VERSION 5.7 ;
  NOWIREEXTENSIONATPIN ON ;
  DIVIDERCHAR "/" ;
  BUSBITCHARS "[]" ;
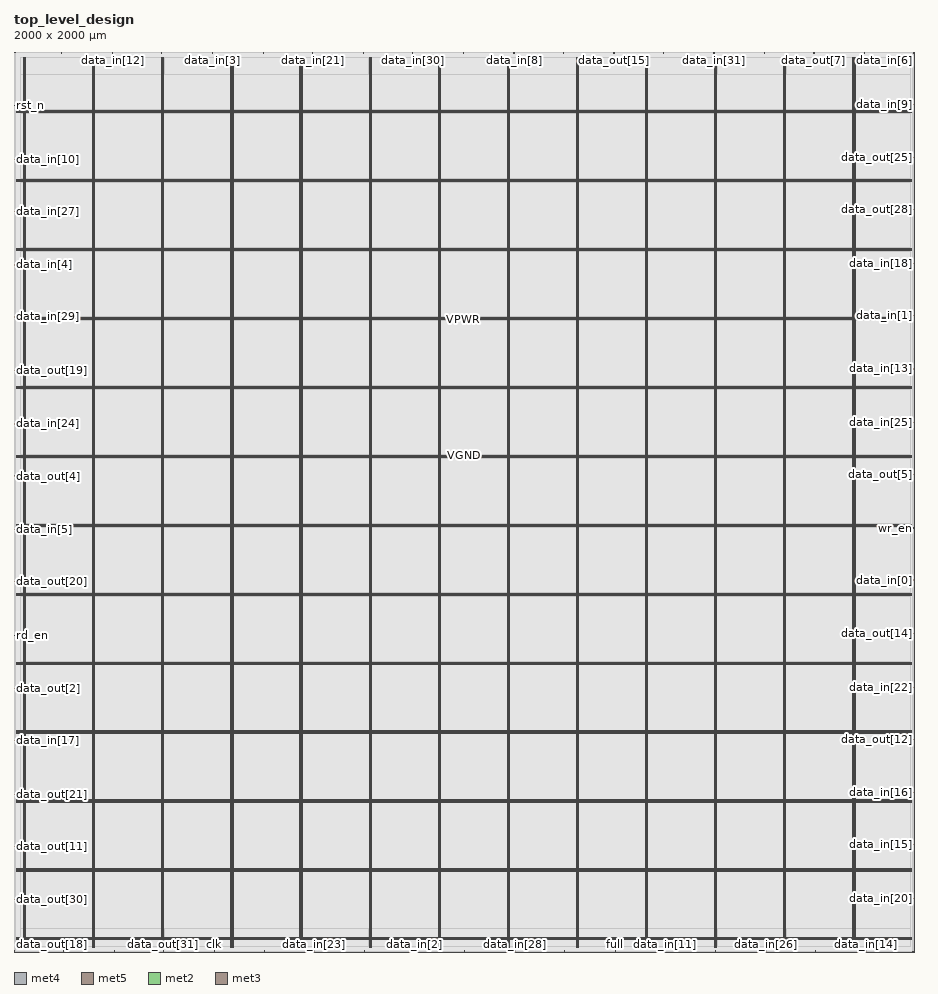
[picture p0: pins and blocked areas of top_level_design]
MACRO top_level_design
  CLASS BLOCK ;
  FOREIGN top_level_design ;
  ORIGIN 0.000 0.000 ;
  SIZE 2000.000 BY 2000.000 ;
  PIN VGND
    DIRECTION INOUT ;
    USE GROUND ;
    PORT
      LAYER met4 ;
        RECT 24.340 10.640 25.940 1988.560 ;
    END
    PORT
      LAYER met4 ;
        RECT 177.940 10.640 179.540 1988.560 ;
    END
    PORT
      LAYER met4 ;
        RECT 331.540 10.640 333.140 1988.560 ;
    END
    PORT
      LAYER met4 ;
        RECT 485.140 10.640 486.740 1988.560 ;
    END
    PORT
      LAYER met4 ;
        RECT 638.740 10.640 640.340 1988.560 ;
    END
    PORT
      LAYER met4 ;
        RECT 792.340 10.640 793.940 1988.560 ;
    END
    PORT
      LAYER met4 ;
        RECT 945.940 10.640 947.540 1988.560 ;
    END
    PORT
      LAYER met4 ;
        RECT 1099.540 10.640 1101.140 1988.560 ;
    END
    PORT
      LAYER met4 ;
        RECT 1253.140 10.640 1254.740 1988.560 ;
    END
    PORT
      LAYER met4 ;
        RECT 1406.740 10.640 1408.340 1988.560 ;
    END
    PORT
      LAYER met4 ;
        RECT 1560.340 10.640 1561.940 1988.560 ;
    END
    PORT
      LAYER met4 ;
        RECT 1713.940 10.640 1715.540 1988.560 ;
    END
    PORT
      LAYER met4 ;
        RECT 1867.540 10.640 1869.140 1988.560 ;
    END
    PORT
      LAYER met5 ;
        RECT 5.280 30.030 1994.340 31.630 ;
    END
    PORT
      LAYER met5 ;
        RECT 5.280 183.210 1994.340 184.810 ;
    END
    PORT
      LAYER met5 ;
        RECT 5.280 336.390 1994.340 337.990 ;
    END
    PORT
      LAYER met5 ;
        RECT 5.280 489.570 1994.340 491.170 ;
    END
    PORT
      LAYER met5 ;
        RECT 5.280 642.750 1994.340 644.350 ;
    END
    PORT
      LAYER met5 ;
        RECT 5.280 795.930 1994.340 797.530 ;
    END
    PORT
      LAYER met5 ;
        RECT 5.280 949.110 1994.340 950.710 ;
    END
    PORT
      LAYER met5 ;
        RECT 5.280 1102.290 1994.340 1103.890 ;
    END
    PORT
      LAYER met5 ;
        RECT 5.280 1255.470 1994.340 1257.070 ;
    END
    PORT
      LAYER met5 ;
        RECT 5.280 1408.650 1994.340 1410.250 ;
    END
    PORT
      LAYER met5 ;
        RECT 5.280 1561.830 1994.340 1563.430 ;
    END
    PORT
      LAYER met5 ;
        RECT 5.280 1715.010 1994.340 1716.610 ;
    END
    PORT
      LAYER met5 ;
        RECT 5.280 1868.190 1994.340 1869.790 ;
    END
  END VGND
  PIN VPWR
    DIRECTION INOUT ;
    USE POWER ;
    PORT
      LAYER met4 ;
        RECT 21.040 10.640 22.640 1988.560 ;
    END
    PORT
      LAYER met4 ;
        RECT 174.640 10.640 176.240 1988.560 ;
    END
    PORT
      LAYER met4 ;
        RECT 328.240 10.640 329.840 1988.560 ;
    END
    PORT
      LAYER met4 ;
        RECT 481.840 10.640 483.440 1988.560 ;
    END
    PORT
      LAYER met4 ;
        RECT 635.440 10.640 637.040 1988.560 ;
    END
    PORT
      LAYER met4 ;
        RECT 789.040 10.640 790.640 1988.560 ;
    END
    PORT
      LAYER met4 ;
        RECT 942.640 10.640 944.240 1988.560 ;
    END
    PORT
      LAYER met4 ;
        RECT 1096.240 10.640 1097.840 1988.560 ;
    END
    PORT
      LAYER met4 ;
        RECT 1249.840 10.640 1251.440 1988.560 ;
    END
    PORT
      LAYER met4 ;
        RECT 1403.440 10.640 1405.040 1988.560 ;
    END
    PORT
      LAYER met4 ;
        RECT 1557.040 10.640 1558.640 1988.560 ;
    END
    PORT
      LAYER met4 ;
        RECT 1710.640 10.640 1712.240 1988.560 ;
    END
    PORT
      LAYER met4 ;
        RECT 1864.240 10.640 1865.840 1988.560 ;
    END
    PORT
      LAYER met5 ;
        RECT 5.280 26.730 1994.340 28.330 ;
    END
    PORT
      LAYER met5 ;
        RECT 5.280 179.910 1994.340 181.510 ;
    END
    PORT
      LAYER met5 ;
        RECT 5.280 333.090 1994.340 334.690 ;
    END
    PORT
      LAYER met5 ;
        RECT 5.280 486.270 1994.340 487.870 ;
    END
    PORT
      LAYER met5 ;
        RECT 5.280 639.450 1994.340 641.050 ;
    END
    PORT
      LAYER met5 ;
        RECT 5.280 792.630 1994.340 794.230 ;
    END
    PORT
      LAYER met5 ;
        RECT 5.280 945.810 1994.340 947.410 ;
    END
    PORT
      LAYER met5 ;
        RECT 5.280 1098.990 1994.340 1100.590 ;
    END
    PORT
      LAYER met5 ;
        RECT 5.280 1252.170 1994.340 1253.770 ;
    END
    PORT
      LAYER met5 ;
        RECT 5.280 1405.350 1994.340 1406.950 ;
    END
    PORT
      LAYER met5 ;
        RECT 5.280 1558.530 1994.340 1560.130 ;
    END
    PORT
      LAYER met5 ;
        RECT 5.280 1711.710 1994.340 1713.310 ;
    END
    PORT
      LAYER met5 ;
        RECT 5.280 1864.890 1994.340 1866.490 ;
    END
  END VPWR
  PIN clk
    DIRECTION INPUT ;
    USE SIGNAL ;
    ANTENNAGATEAREA 1.286700 ;
    ANTENNADIFFAREA 0.434700 ;
    PORT
      LAYER met2 ;
        RECT 444.450 0.000 444.730 4.000 ;
    END
  END clk
  PIN data_in[0]
    DIRECTION INPUT ;
    USE SIGNAL ;
    ANTENNAGATEAREA 0.495000 ;
    PORT
      LAYER met3 ;
        RECT 1996.000 826.240 2000.000 826.840 ;
    END
  END data_in[0]
  PIN data_in[10]
    DIRECTION INPUT ;
    USE SIGNAL ;
    ANTENNAGATEAREA 0.990000 ;
    PORT
      LAYER met3 ;
        RECT 0.000 1761.240 4.000 1761.840 ;
    END
  END data_in[10]
  PIN data_in[11]
    DIRECTION INPUT ;
    USE SIGNAL ;
    ANTENNAGATEAREA 0.742500 ;
    PORT
      LAYER met2 ;
        RECT 1445.870 0.000 1446.150 4.000 ;
    END
  END data_in[11]
  PIN data_in[12]
    DIRECTION INPUT ;
    USE SIGNAL ;
    ANTENNAGATEAREA 0.990000 ;
    PORT
      LAYER met2 ;
        RECT 219.050 1996.000 219.330 2000.000 ;
    END
  END data_in[12]
  PIN data_in[13]
    DIRECTION INPUT ;
    USE SIGNAL ;
    ANTENNAGATEAREA 0.426000 ;
    PORT
      LAYER met3 ;
        RECT 1996.000 1295.440 2000.000 1296.040 ;
    END
  END data_in[13]
  PIN data_in[14]
    DIRECTION INPUT ;
    USE SIGNAL ;
    ANTENNAGATEAREA 0.990000 ;
    PORT
      LAYER met2 ;
        RECT 1893.450 0.000 1893.730 4.000 ;
    END
  END data_in[14]
  PIN data_in[15]
    DIRECTION INPUT ;
    USE SIGNAL ;
    ANTENNAGATEAREA 0.852000 ;
    PORT
      LAYER met3 ;
        RECT 1996.000 238.040 2000.000 238.640 ;
    END
  END data_in[15]
  PIN data_in[16]
    DIRECTION INPUT ;
    USE SIGNAL ;
    ANTENNAGATEAREA 0.852000 ;
    PORT
      LAYER met3 ;
        RECT 1996.000 353.640 2000.000 354.240 ;
    END
  END data_in[16]
  PIN data_in[17]
    DIRECTION INPUT ;
    USE SIGNAL ;
    ANTENNAGATEAREA 0.990000 ;
    PORT
      LAYER met3 ;
        RECT 0.000 469.240 4.000 469.840 ;
    END
  END data_in[17]
  PIN data_in[18]
    DIRECTION INPUT ;
    USE SIGNAL ;
    ANTENNAGATEAREA 0.495000 ;
    PORT
      LAYER met3 ;
        RECT 1996.000 1530.040 2000.000 1530.640 ;
    END
  END data_in[18]
  PIN data_in[19]
    DIRECTION INPUT ;
    USE SIGNAL ;
    ANTENNAGATEAREA 0.990000 ;
    PORT
      LAYER met3 ;
        RECT 0.000 1999.240 4.000 1999.840 ;
    END
  END data_in[19]
  PIN data_in[1]
    DIRECTION INPUT ;
    USE SIGNAL ;
    ANTENNAGATEAREA 0.247500 ;
    PORT
      LAYER met3 ;
        RECT 1996.000 1414.440 2000.000 1415.040 ;
    END
  END data_in[1]
  PIN data_in[20]
    DIRECTION INPUT ;
    USE SIGNAL ;
    ANTENNAGATEAREA 0.990000 ;
    PORT
      LAYER met3 ;
        RECT 1996.000 119.040 2000.000 119.640 ;
    END
  END data_in[20]
  PIN data_in[21]
    DIRECTION INPUT ;
    USE SIGNAL ;
    ANTENNAGATEAREA 0.990000 ;
    PORT
      LAYER met2 ;
        RECT 663.410 1996.000 663.690 2000.000 ;
    END
  END data_in[21]
  PIN data_in[22]
    DIRECTION INPUT ;
    USE SIGNAL ;
    ANTENNAGATEAREA 0.742500 ;
    PORT
      LAYER met3 ;
        RECT 1996.000 588.240 2000.000 588.840 ;
    END
  END data_in[22]
  PIN data_in[23]
    DIRECTION INPUT ;
    USE SIGNAL ;
    ANTENNAGATEAREA 0.990000 ;
    PORT
      LAYER met2 ;
        RECT 666.630 0.000 666.910 4.000 ;
    END
  END data_in[23]
  PIN data_in[24]
    DIRECTION INPUT ;
    USE SIGNAL ;
    ANTENNAGATEAREA 0.990000 ;
    PORT
      LAYER met3 ;
        RECT 0.000 1173.040 4.000 1173.640 ;
    END
  END data_in[24]
  PIN data_in[25]
    DIRECTION INPUT ;
    USE SIGNAL ;
    ANTENNAGATEAREA 0.247500 ;
    PORT
      LAYER met3 ;
        RECT 1996.000 1176.440 2000.000 1177.040 ;
    END
  END data_in[25]
  PIN data_in[26]
    DIRECTION INPUT ;
    USE SIGNAL ;
    ANTENNAGATEAREA 0.852000 ;
    PORT
      LAYER met2 ;
        RECT 1671.270 0.000 1671.550 4.000 ;
    END
  END data_in[26]
  PIN data_in[27]
    DIRECTION INPUT ;
    USE SIGNAL ;
    ANTENNAGATEAREA 0.990000 ;
    PORT
      LAYER met3 ;
        RECT 0.000 1645.640 4.000 1646.240 ;
    END
  END data_in[27]
  PIN data_in[28]
    DIRECTION INPUT ;
    USE SIGNAL ;
    ANTENNAGATEAREA 0.852000 ;
    PORT
      LAYER met2 ;
        RECT 1114.210 0.000 1114.490 4.000 ;
    END
  END data_in[28]
  PIN data_in[29]
    DIRECTION INPUT ;
    USE SIGNAL ;
    ANTENNAGATEAREA 0.990000 ;
    PORT
      LAYER met3 ;
        RECT 0.000 1411.040 4.000 1411.640 ;
    END
  END data_in[29]
  PIN data_in[2]
    DIRECTION INPUT ;
    USE SIGNAL ;
    ANTENNAGATEAREA 0.990000 ;
    PORT
      LAYER met2 ;
        RECT 888.810 0.000 889.090 4.000 ;
    END
  END data_in[2]
  PIN data_in[30]
    DIRECTION INPUT ;
    USE SIGNAL ;
    ANTENNAGATEAREA 0.852000 ;
    PORT
      LAYER met2 ;
        RECT 885.590 1996.000 885.870 2000.000 ;
    END
  END data_in[30]
  PIN data_in[31]
    DIRECTION INPUT ;
    USE SIGNAL ;
    ANTENNAGATEAREA 0.495000 ;
    PORT
      LAYER met2 ;
        RECT 1555.350 1996.000 1555.630 2000.000 ;
    END
  END data_in[31]
  PIN data_in[3]
    DIRECTION INPUT ;
    USE SIGNAL ;
    ANTENNAGATEAREA 0.990000 ;
    PORT
      LAYER met2 ;
        RECT 441.230 1996.000 441.510 2000.000 ;
    END
  END data_in[3]
  PIN data_in[4]
    DIRECTION INPUT ;
    USE SIGNAL ;
    ANTENNAGATEAREA 0.990000 ;
    PORT
      LAYER met3 ;
        RECT 0.000 1526.640 4.000 1527.240 ;
    END
  END data_in[4]
  PIN data_in[5]
    DIRECTION INPUT ;
    USE SIGNAL ;
    ANTENNAGATEAREA 0.990000 ;
    PORT
      LAYER met3 ;
        RECT 0.000 938.440 4.000 939.040 ;
    END
  END data_in[5]
  PIN data_in[6]
    DIRECTION INPUT ;
    USE SIGNAL ;
    ANTENNAGATEAREA 0.742500 ;
    PORT
      LAYER met2 ;
        RECT 1999.710 1996.000 1999.990 2000.000 ;
    END
  END data_in[6]
  PIN data_in[7]
    DIRECTION INPUT ;
    USE SIGNAL ;
    ANTENNAGATEAREA 0.990000 ;
    PORT
      LAYER met2 ;
        RECT 1780.750 0.000 1781.030 4.000 ;
    END
  END data_in[7]
  PIN data_in[8]
    DIRECTION INPUT ;
    USE SIGNAL ;
    ANTENNAGATEAREA 0.495000 ;
    PORT
      LAYER met2 ;
        RECT 1110.990 1996.000 1111.270 2000.000 ;
    END
  END data_in[8]
  PIN data_in[9]
    DIRECTION INPUT ;
    USE SIGNAL ;
    ANTENNAGATEAREA 0.742500 ;
    PORT
      LAYER met3 ;
        RECT 1996.000 1883.640 2000.000 1884.240 ;
    END
  END data_in[9]
  PIN data_out[0]
    DIRECTION OUTPUT TRISTATE ;
    USE SIGNAL ;
    ANTENNADIFFAREA 0.795200 ;
    PORT
      LAYER met2 ;
        RECT 1558.570 0.000 1558.850 4.000 ;
    END
  END data_out[0]
  PIN data_out[10]
    DIRECTION OUTPUT TRISTATE ;
    USE SIGNAL ;
    ANTENNADIFFAREA 0.795200 ;
    PORT
      LAYER met2 ;
        RECT 998.290 1996.000 998.570 2000.000 ;
    END
  END data_out[10]
  PIN data_out[11]
    DIRECTION OUTPUT TRISTATE ;
    USE SIGNAL ;
    ANTENNADIFFAREA 0.795200 ;
    PORT
      LAYER met3 ;
        RECT 0.000 234.640 4.000 235.240 ;
    END
  END data_out[11]
  PIN data_out[12]
    DIRECTION OUTPUT TRISTATE ;
    USE SIGNAL ;
    ANTENNADIFFAREA 0.445500 ;
    PORT
      LAYER met3 ;
        RECT 1996.000 472.640 2000.000 473.240 ;
    END
  END data_out[12]
  PIN data_out[13]
    DIRECTION OUTPUT TRISTATE ;
    USE SIGNAL ;
    ANTENNADIFFAREA 0.795200 ;
    PORT
      LAYER met2 ;
        RECT 1223.690 0.000 1223.970 4.000 ;
    END
  END data_out[13]
  PIN data_out[14]
    DIRECTION OUTPUT TRISTATE ;
    USE SIGNAL ;
    ANTENNADIFFAREA 0.445500 ;
    PORT
      LAYER met3 ;
        RECT 1996.000 707.240 2000.000 707.840 ;
    END
  END data_out[14]
  PIN data_out[15]
    DIRECTION OUTPUT TRISTATE ;
    USE SIGNAL ;
    ANTENNADIFFAREA 0.795200 ;
    PORT
      LAYER met2 ;
        RECT 1333.170 1996.000 1333.450 2000.000 ;
    END
  END data_out[15]
  PIN data_out[16]
    DIRECTION OUTPUT TRISTATE ;
    USE SIGNAL ;
    ANTENNADIFFAREA 0.795200 ;
    PORT
      LAYER met2 ;
        RECT 1442.650 1996.000 1442.930 2000.000 ;
    END
  END data_out[16]
  PIN data_out[17]
    DIRECTION OUTPUT TRISTATE ;
    USE SIGNAL ;
    ANTENNADIFFAREA 0.795200 ;
    PORT
      LAYER met2 ;
        RECT 106.350 1996.000 106.630 2000.000 ;
    END
  END data_out[17]
  PIN data_out[18]
    DIRECTION OUTPUT TRISTATE ;
    USE SIGNAL ;
    ANTENNADIFFAREA 0.795200 ;
    PORT
      LAYER met2 ;
        RECT 0.090 0.000 0.370 4.000 ;
    END
  END data_out[18]
  PIN data_out[19]
    DIRECTION OUTPUT TRISTATE ;
    USE SIGNAL ;
    ANTENNADIFFAREA 0.795200 ;
    PORT
      LAYER met3 ;
        RECT 0.000 1292.040 4.000 1292.640 ;
    END
  END data_out[19]
  PIN data_out[1]
    DIRECTION OUTPUT TRISTATE ;
    USE SIGNAL ;
    ANTENNADIFFAREA 0.795200 ;
    PORT
      LAYER met2 ;
        RECT 1220.470 1996.000 1220.750 2000.000 ;
    END
  END data_out[1]
  PIN data_out[20]
    DIRECTION OUTPUT TRISTATE ;
    USE SIGNAL ;
    ANTENNADIFFAREA 0.795200 ;
    PORT
      LAYER met3 ;
        RECT 0.000 822.840 4.000 823.440 ;
    END
  END data_out[20]
  PIN data_out[21]
    DIRECTION OUTPUT TRISTATE ;
    USE SIGNAL ;
    ANTENNADIFFAREA 0.795200 ;
    PORT
      LAYER met3 ;
        RECT 0.000 350.240 4.000 350.840 ;
    END
  END data_out[21]
  PIN data_out[22]
    DIRECTION OUTPUT TRISTATE ;
    USE SIGNAL ;
    ANTENNADIFFAREA 0.795200 ;
    PORT
      LAYER met2 ;
        RECT 776.110 1996.000 776.390 2000.000 ;
    END
  END data_out[22]
  PIN data_out[23]
    DIRECTION OUTPUT TRISTATE ;
    USE SIGNAL ;
    ANTENNADIFFAREA 0.795200 ;
    PORT
      LAYER met2 ;
        RECT 222.270 0.000 222.550 4.000 ;
    END
  END data_out[23]
  PIN data_out[24]
    DIRECTION OUTPUT TRISTATE ;
    USE SIGNAL ;
    ANTENNADIFFAREA 0.795200 ;
    PORT
      LAYER met2 ;
        RECT 109.570 0.000 109.850 4.000 ;
    END
  END data_out[24]
  PIN data_out[25]
    DIRECTION OUTPUT TRISTATE ;
    USE SIGNAL ;
    ANTENNADIFFAREA 0.795200 ;
    PORT
      LAYER met3 ;
        RECT 1996.000 1764.640 2000.000 1765.240 ;
    END
  END data_out[25]
  PIN data_out[26]
    DIRECTION OUTPUT TRISTATE ;
    USE SIGNAL ;
    ANTENNADIFFAREA 0.795200 ;
    PORT
      LAYER met2 ;
        RECT 1890.230 1996.000 1890.510 2000.000 ;
    END
  END data_out[26]
  PIN data_out[27]
    DIRECTION OUTPUT TRISTATE ;
    USE SIGNAL ;
    ANTENNADIFFAREA 0.795200 ;
    PORT
      LAYER met2 ;
        RECT 779.330 0.000 779.610 4.000 ;
    END
  END data_out[27]
  PIN data_out[28]
    DIRECTION OUTPUT TRISTATE ;
    USE SIGNAL ;
    ANTENNADIFFAREA 0.795200 ;
    PORT
      LAYER met3 ;
        RECT 1996.000 1649.040 2000.000 1649.640 ;
    END
  END data_out[28]
  PIN data_out[29]
    DIRECTION OUTPUT TRISTATE ;
    USE SIGNAL ;
    ANTENNADIFFAREA 0.795200 ;
    PORT
      LAYER met3 ;
        RECT 1996.000 0.040 2000.000 0.640 ;
    END
  END data_out[29]
  PIN data_out[2]
    DIRECTION OUTPUT TRISTATE ;
    USE SIGNAL ;
    ANTENNADIFFAREA 0.795200 ;
    PORT
      LAYER met3 ;
        RECT 0.000 584.840 4.000 585.440 ;
    END
  END data_out[2]
  PIN data_out[30]
    DIRECTION OUTPUT TRISTATE ;
    USE SIGNAL ;
    ANTENNADIFFAREA 0.795200 ;
    PORT
      LAYER met3 ;
        RECT 0.000 115.640 4.000 116.240 ;
    END
  END data_out[30]
  PIN data_out[31]
    DIRECTION OUTPUT TRISTATE ;
    USE SIGNAL ;
    ANTENNADIFFAREA 0.795200 ;
    PORT
      LAYER met2 ;
        RECT 331.750 0.000 332.030 4.000 ;
    END
  END data_out[31]
  PIN data_out[3]
    DIRECTION OUTPUT TRISTATE ;
    USE SIGNAL ;
    ANTENNADIFFAREA 0.795200 ;
    PORT
      LAYER met2 ;
        RECT 557.150 0.000 557.430 4.000 ;
    END
  END data_out[3]
  PIN data_out[4]
    DIRECTION OUTPUT TRISTATE ;
    USE SIGNAL ;
    ANTENNADIFFAREA 0.795200 ;
    PORT
      LAYER met3 ;
        RECT 0.000 1057.440 4.000 1058.040 ;
    END
  END data_out[4]
  PIN data_out[5]
    DIRECTION OUTPUT TRISTATE ;
    USE SIGNAL ;
    ANTENNADIFFAREA 0.445500 ;
    PORT
      LAYER met3 ;
        RECT 1996.000 1060.840 2000.000 1061.440 ;
    END
  END data_out[5]
  PIN data_out[6]
    DIRECTION OUTPUT TRISTATE ;
    USE SIGNAL ;
    ANTENNADIFFAREA 0.795200 ;
    PORT
      LAYER met2 ;
        RECT 1001.510 0.000 1001.790 4.000 ;
    END
  END data_out[6]
  PIN data_out[7]
    DIRECTION OUTPUT TRISTATE ;
    USE SIGNAL ;
    ANTENNADIFFAREA 0.795200 ;
    PORT
      LAYER met2 ;
        RECT 1777.530 1996.000 1777.810 2000.000 ;
    END
  END data_out[7]
  PIN data_out[8]
    DIRECTION OUTPUT TRISTATE ;
    USE SIGNAL ;
    ANTENNADIFFAREA 0.795200 ;
    PORT
      LAYER met2 ;
        RECT 1668.050 1996.000 1668.330 2000.000 ;
    END
  END data_out[8]
  PIN data_out[9]
    DIRECTION OUTPUT TRISTATE ;
    USE SIGNAL ;
    ANTENNADIFFAREA 0.795200 ;
    PORT
      LAYER met2 ;
        RECT 328.530 1996.000 328.810 2000.000 ;
    END
  END data_out[9]
  PIN empty
    DIRECTION OUTPUT TRISTATE ;
    USE SIGNAL ;
    ANTENNADIFFAREA 0.795200 ;
    PORT
      LAYER met2 ;
        RECT 553.930 1996.000 554.210 2000.000 ;
    END
  END empty
  PIN full
    DIRECTION OUTPUT TRISTATE ;
    USE SIGNAL ;
    ANTENNADIFFAREA 0.795200 ;
    PORT
      LAYER met2 ;
        RECT 1336.390 0.000 1336.670 4.000 ;
    END
  END full
  PIN rd_en
    DIRECTION INPUT ;
    USE SIGNAL ;
    ANTENNAGATEAREA 0.426000 ;
    PORT
      LAYER met3 ;
        RECT 0.000 703.840 4.000 704.440 ;
    END
  END rd_en
  PIN rst_n
    DIRECTION INPUT ;
    USE SIGNAL ;
    ANTENNAGATEAREA 0.742500 ;
    PORT
      LAYER met3 ;
        RECT 0.000 1880.240 4.000 1880.840 ;
    END
  END rst_n
  PIN wr_en
    DIRECTION INPUT ;
    USE SIGNAL ;
    ANTENNAGATEAREA 0.426000 ;
    PORT
      LAYER met3 ;
        RECT 1996.000 941.840 2000.000 942.440 ;
    END
  END wr_en
  OBS
      LAYER li1 ;
        RECT 5.520 10.795 1994.100 1988.405 ;
      LAYER met1 ;
        RECT 0.070 10.640 1999.550 1988.560 ;
      LAYER met2 ;
        RECT 0.100 1995.720 106.070 1999.725 ;
        RECT 106.910 1995.720 218.770 1999.725 ;
        RECT 219.610 1995.720 328.250 1999.725 ;
        RECT 329.090 1995.720 440.950 1999.725 ;
        RECT 441.790 1995.720 553.650 1999.725 ;
        RECT 554.490 1995.720 663.130 1999.725 ;
        RECT 663.970 1995.720 775.830 1999.725 ;
        RECT 776.670 1995.720 885.310 1999.725 ;
        RECT 886.150 1995.720 998.010 1999.725 ;
        RECT 998.850 1995.720 1110.710 1999.725 ;
        RECT 1111.550 1995.720 1220.190 1999.725 ;
        RECT 1221.030 1995.720 1332.890 1999.725 ;
        RECT 1333.730 1995.720 1442.370 1999.725 ;
        RECT 1443.210 1995.720 1555.070 1999.725 ;
        RECT 1555.910 1995.720 1667.770 1999.725 ;
        RECT 1668.610 1995.720 1777.250 1999.725 ;
        RECT 1778.090 1995.720 1889.950 1999.725 ;
        RECT 1890.790 1995.720 1999.430 1999.725 ;
        RECT 0.100 4.280 1999.920 1995.720 ;
        RECT 0.650 0.155 109.290 4.280 ;
        RECT 110.130 0.155 221.990 4.280 ;
        RECT 222.830 0.155 331.470 4.280 ;
        RECT 332.310 0.155 444.170 4.280 ;
        RECT 445.010 0.155 556.870 4.280 ;
        RECT 557.710 0.155 666.350 4.280 ;
        RECT 667.190 0.155 779.050 4.280 ;
        RECT 779.890 0.155 888.530 4.280 ;
        RECT 889.370 0.155 1001.230 4.280 ;
        RECT 1002.070 0.155 1113.930 4.280 ;
        RECT 1114.770 0.155 1223.410 4.280 ;
        RECT 1224.250 0.155 1336.110 4.280 ;
        RECT 1336.950 0.155 1445.590 4.280 ;
        RECT 1446.430 0.155 1558.290 4.280 ;
        RECT 1559.130 0.155 1670.990 4.280 ;
        RECT 1671.830 0.155 1780.470 4.280 ;
        RECT 1781.310 0.155 1893.170 4.280 ;
        RECT 1894.010 0.155 1999.920 4.280 ;
      LAYER met3 ;
        RECT 4.400 1998.840 1996.000 1999.705 ;
        RECT 3.990 1884.640 1996.000 1998.840 ;
        RECT 3.990 1883.240 1995.600 1884.640 ;
        RECT 3.990 1881.240 1996.000 1883.240 ;
        RECT 4.400 1879.840 1996.000 1881.240 ;
        RECT 3.990 1765.640 1996.000 1879.840 ;
        RECT 3.990 1764.240 1995.600 1765.640 ;
        RECT 3.990 1762.240 1996.000 1764.240 ;
        RECT 4.400 1760.840 1996.000 1762.240 ;
        RECT 3.990 1650.040 1996.000 1760.840 ;
        RECT 3.990 1648.640 1995.600 1650.040 ;
        RECT 3.990 1646.640 1996.000 1648.640 ;
        RECT 4.400 1645.240 1996.000 1646.640 ;
        RECT 3.990 1531.040 1996.000 1645.240 ;
        RECT 3.990 1529.640 1995.600 1531.040 ;
        RECT 3.990 1527.640 1996.000 1529.640 ;
        RECT 4.400 1526.240 1996.000 1527.640 ;
        RECT 3.990 1415.440 1996.000 1526.240 ;
        RECT 3.990 1414.040 1995.600 1415.440 ;
        RECT 3.990 1412.040 1996.000 1414.040 ;
        RECT 4.400 1410.640 1996.000 1412.040 ;
        RECT 3.990 1296.440 1996.000 1410.640 ;
        RECT 3.990 1295.040 1995.600 1296.440 ;
        RECT 3.990 1293.040 1996.000 1295.040 ;
        RECT 4.400 1291.640 1996.000 1293.040 ;
        RECT 3.990 1177.440 1996.000 1291.640 ;
        RECT 3.990 1176.040 1995.600 1177.440 ;
        RECT 3.990 1174.040 1996.000 1176.040 ;
        RECT 4.400 1172.640 1996.000 1174.040 ;
        RECT 3.990 1061.840 1996.000 1172.640 ;
        RECT 3.990 1060.440 1995.600 1061.840 ;
        RECT 3.990 1058.440 1996.000 1060.440 ;
        RECT 4.400 1057.040 1996.000 1058.440 ;
        RECT 3.990 942.840 1996.000 1057.040 ;
        RECT 3.990 941.440 1995.600 942.840 ;
        RECT 3.990 939.440 1996.000 941.440 ;
        RECT 4.400 938.040 1996.000 939.440 ;
        RECT 3.990 827.240 1996.000 938.040 ;
        RECT 3.990 825.840 1995.600 827.240 ;
        RECT 3.990 823.840 1996.000 825.840 ;
        RECT 4.400 822.440 1996.000 823.840 ;
        RECT 3.990 708.240 1996.000 822.440 ;
        RECT 3.990 706.840 1995.600 708.240 ;
        RECT 3.990 704.840 1996.000 706.840 ;
        RECT 4.400 703.440 1996.000 704.840 ;
        RECT 3.990 589.240 1996.000 703.440 ;
        RECT 3.990 587.840 1995.600 589.240 ;
        RECT 3.990 585.840 1996.000 587.840 ;
        RECT 4.400 584.440 1996.000 585.840 ;
        RECT 3.990 473.640 1996.000 584.440 ;
        RECT 3.990 472.240 1995.600 473.640 ;
        RECT 3.990 470.240 1996.000 472.240 ;
        RECT 4.400 468.840 1996.000 470.240 ;
        RECT 3.990 354.640 1996.000 468.840 ;
        RECT 3.990 353.240 1995.600 354.640 ;
        RECT 3.990 351.240 1996.000 353.240 ;
        RECT 4.400 349.840 1996.000 351.240 ;
        RECT 3.990 239.040 1996.000 349.840 ;
        RECT 3.990 237.640 1995.600 239.040 ;
        RECT 3.990 235.640 1996.000 237.640 ;
        RECT 4.400 234.240 1996.000 235.640 ;
        RECT 3.990 120.040 1996.000 234.240 ;
        RECT 3.990 118.640 1995.600 120.040 ;
        RECT 3.990 116.640 1996.000 118.640 ;
        RECT 4.400 115.240 1996.000 116.640 ;
        RECT 3.990 1.040 1996.000 115.240 ;
        RECT 3.990 0.175 1995.600 1.040 ;
      LAYER met4 ;
        RECT 15.510 11.735 20.640 1986.785 ;
        RECT 23.040 11.735 23.940 1986.785 ;
        RECT 26.340 11.735 174.240 1986.785 ;
        RECT 176.640 11.735 177.540 1986.785 ;
        RECT 179.940 11.735 327.840 1986.785 ;
        RECT 330.240 11.735 331.140 1986.785 ;
        RECT 333.540 11.735 481.440 1986.785 ;
        RECT 483.840 11.735 484.740 1986.785 ;
        RECT 487.140 11.735 635.040 1986.785 ;
        RECT 637.440 11.735 638.340 1986.785 ;
        RECT 640.740 11.735 788.640 1986.785 ;
        RECT 791.040 11.735 791.940 1986.785 ;
        RECT 794.340 11.735 942.240 1986.785 ;
        RECT 944.640 11.735 945.540 1986.785 ;
        RECT 947.940 11.735 1095.840 1986.785 ;
        RECT 1098.240 11.735 1099.140 1986.785 ;
        RECT 1101.540 11.735 1249.440 1986.785 ;
        RECT 1251.840 11.735 1252.740 1986.785 ;
        RECT 1255.140 11.735 1403.040 1986.785 ;
        RECT 1405.440 11.735 1406.340 1986.785 ;
        RECT 1408.740 11.735 1556.640 1986.785 ;
        RECT 1559.040 11.735 1559.940 1986.785 ;
        RECT 1562.340 11.735 1710.240 1986.785 ;
        RECT 1712.640 11.735 1713.540 1986.785 ;
        RECT 1715.940 11.735 1863.840 1986.785 ;
        RECT 1866.240 11.735 1867.140 1986.785 ;
        RECT 1869.540 11.735 1992.850 1986.785 ;
      LAYER met5 ;
        RECT 15.300 1871.390 1993.060 1950.700 ;
        RECT 15.300 1718.210 1993.060 1863.290 ;
        RECT 15.300 1565.030 1993.060 1710.110 ;
        RECT 15.300 1411.850 1993.060 1556.930 ;
        RECT 15.300 1258.670 1993.060 1403.750 ;
        RECT 15.300 1105.490 1993.060 1250.570 ;
        RECT 15.300 952.310 1993.060 1097.390 ;
        RECT 15.300 799.130 1993.060 944.210 ;
        RECT 15.300 645.950 1993.060 791.030 ;
        RECT 15.300 492.770 1993.060 637.850 ;
        RECT 15.300 339.590 1993.060 484.670 ;
        RECT 15.300 186.410 1993.060 331.490 ;
        RECT 15.300 51.900 1993.060 178.310 ;
  END
END top_level_design
END LIBRARY

